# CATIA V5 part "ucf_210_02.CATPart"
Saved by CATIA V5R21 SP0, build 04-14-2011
Part number: ucf_210_02
Bounding box of the stored display mesh (mm): x -66.02 to -51.559, y -4.7 to -1.341, z -1.647 to 1.674
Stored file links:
  C:\TPO v2\SharedFS\Outgoing\ucf_210_02.CATPart

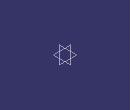
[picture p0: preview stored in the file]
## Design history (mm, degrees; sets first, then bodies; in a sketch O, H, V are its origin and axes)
AxisSystem1: origin (0, 0, 0), X (1, 0, 0), Y (0, 1, 0), Z (0, 0, 1)
Body1 "ucf_210_02" (main body)
  Solid1: solid without history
